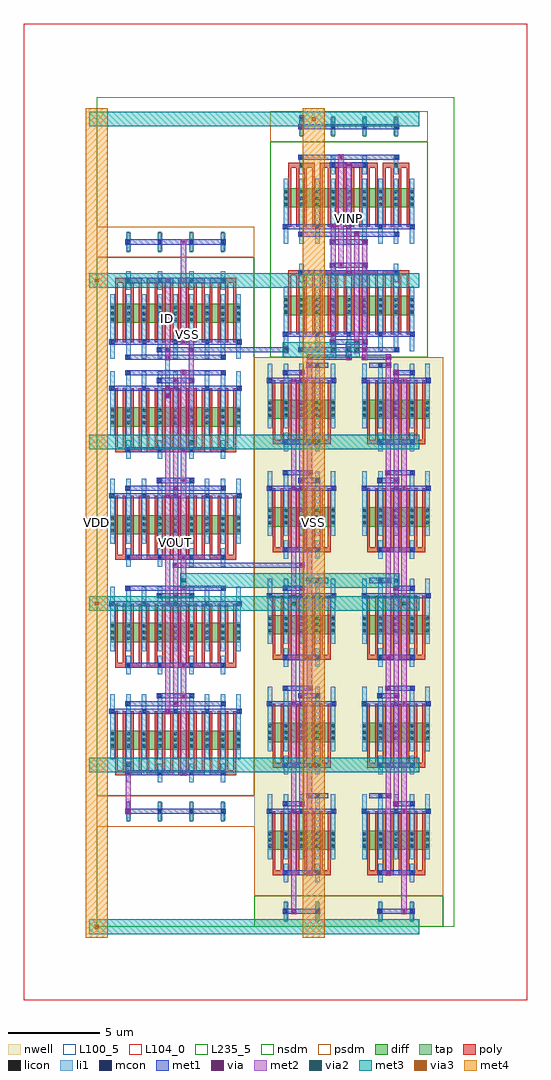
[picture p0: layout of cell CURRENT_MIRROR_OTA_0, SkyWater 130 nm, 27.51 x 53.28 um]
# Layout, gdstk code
from math import pi, radians
import gdstk
lib = gdstk.Library(unit=1e-6, precision=1e-09)
def R(c, l, rs):  # rectangles x0, y0, x1, y1
    for r in rs: c.add(gdstk.rectangle(r[:2], r[2:], *l))
def A(c, l, x, y, w, h, nx, ny, dx, dy):  # array of equal rectangles
    R(c, l, [(x+i*dx, y+j*dy, x+i*dx+w, y+j*dy+h) for i in range(nx) for j in range(ny)])
def P(c, l, *ps):  # polygons
    for p in ps: c.add(gdstk.Polygon(p, *l))
nwell = (64, 20)
diff = (65, 20)
tap = (65, 44)
poly = (66, 20)
licon = (66, 44)
li1 = (67, 20)
mcon = (67, 44)
met1 = (68, 20)
via = (68, 44)
met2 = (69, 20)
via2 = (69, 44)
met3 = (70, 20)
via3 = (70, 44)
met4 = (71, 20)
nsdm = (93, 44)
psdm = (94, 20)
L100_5 = (100, 5)
L104_0 = (104, 0)
L235_5 = (235, 5)

scm_nmos_5643887_x2_y1_1 = lib.new_cell('SCM_NMOS_5643887_X2_Y1_1724778739')
R(scm_nmos_5643887_x2_y1_1, diff, [(0.735,2.31,7.865,3.36)])
A(scm_nmos_5643887_x2_y1_1, tap, 1.635, 6.16, 0.17, 1.12, 4, 1, 1.72, 0)
A(scm_nmos_5643887_x2_y1_1, poly, 1, 1.26, 0.15, 3.36, 16, 1, 0.43, 0)
A(scm_nmos_5643887_x2_y1_1, poly, 1, 4.485, 1.44, 0.27, 4, 1, 1.72, 0)
A(scm_nmos_5643887_x2_y1_1, licon, 0.775, 2.39, 0.17, 0.17, 3, 3, 0.86, 0.34)
A(scm_nmos_5643887_x2_y1_1, licon, 2.495, 2.39, 0.17, 0.17, 3, 3, 0.86, 0.34)
A(scm_nmos_5643887_x2_y1_1, licon, 4.215, 2.39, 0.17, 0.17, 3, 3, 0.86, 0.34)
A(scm_nmos_5643887_x2_y1_1, licon, 5.935, 2.39, 0.17, 0.17, 3, 3, 0.86, 0.34)
A(scm_nmos_5643887_x2_y1_1, licon, 1.635, 4.535, 0.17, 0.17, 4, 2, 1.72, 2.1)
A(scm_nmos_5643887_x2_y1_1, li1, 0.735, 0.335, 0.25, 3.53, 9, 1, 0.86, 0)
A(scm_nmos_5643887_x2_y1_1, li1, 1.595, 4.115, 0.25, 1.01, 4, 2, 1.72, 2.1)
A(scm_nmos_5643887_x2_y1_1, mcon, 0.775, 1.175, 0.17, 0.17, 5, 1, 1.72, 0)
A(scm_nmos_5643887_x2_y1_1, mcon, 1.635, 4.535, 0.17, 0.17, 4, 2, 1.72, 2.1)
R(scm_nmos_5643887_x2_y1_1, mcon, [(1.635,0.335,1.805,0.505), (6.795,0.335,6.965,0.505), (3.355,0.755,3.525,0.925), (5.075,0.755,5.245,0.925)])
R(scm_nmos_5643887_x2_y1_1, met1, [(1.55,0.28,7.05,0.56), (3.27,0.7,5.33,0.98), (0.69,1.12,7.91,1.4), (1.55,4.48,7.05,4.76), (1.55,6.58,7.05,6.86)])
R(scm_nmos_5643887_x2_y1_1, via, [(3.795,0.345,3.945,0.495), (4.655,1.185,4.805,1.335), (3.795,4.545,3.945,4.695), (4.655,6.645,4.805,6.795)])
R(scm_nmos_5643887_x2_y1_1, met2, [(3.73,0.26,4.01,4.78), (4.59,1.1,4.87,6.88)])
R(scm_nmos_5643887_x2_y1_1, nsdm, [(0,0,8.6,5.88)])
R(scm_nmos_5643887_x2_y1_1, psdm, [(0,5.88,8.6,7.56)])
R(scm_nmos_5643887_x2_y1_1, L100_5, [(0,0,8.6,7.56)])

scm_pmos_85912433_x1_y5_ = lib.new_cell('SCM_PMOS_85912433_X1_Y5_1724778741')
R(scm_pmos_85912433_x1_y5_, nwell, [(0,0,5.16,31.08)])
A(scm_pmos_85912433_x1_y5_, diff, 0.735, 2.31, 3.69, 1.05, 1, 5, 0, 5.88)
R(scm_pmos_85912433_x1_y5_, tap, [(1.635,29.68,1.805,30.8), (3.355,29.68,3.525,30.8)])
A(scm_pmos_85912433_x1_y5_, poly, 1, 1.26, 0.15, 3.36, 8, 5, 0.43, 5.88)
A(scm_pmos_85912433_x1_y5_, poly, 1, 4.485, 1.44, 0.27, 1, 5, 0, 5.88)
A(scm_pmos_85912433_x1_y5_, poly, 2.72, 4.485, 1.44, 0.27, 1, 5, 0, 5.88)
A(scm_pmos_85912433_x1_y5_, licon, 0.775, 2.39, 0.17, 0.17, 3, 3, 0.86, 0.34)
A(scm_pmos_85912433_x1_y5_, licon, 2.495, 2.39, 0.17, 0.17, 3, 3, 0.86, 0.34)
A(scm_pmos_85912433_x1_y5_, licon, 1.635, 4.535, 0.17, 0.17, 1, 5, 0, 5.88)
A(scm_pmos_85912433_x1_y5_, licon, 3.355, 4.535, 0.17, 0.17, 1, 5, 0, 5.88)
A(scm_pmos_85912433_x1_y5_, licon, 0.775, 8.27, 0.17, 0.17, 3, 3, 0.86, 0.34)
A(scm_pmos_85912433_x1_y5_, licon, 2.495, 8.27, 0.17, 0.17, 3, 3, 0.86, 0.34)
A(scm_pmos_85912433_x1_y5_, licon, 0.775, 14.15, 0.17, 0.17, 3, 3, 0.86, 0.34)
A(scm_pmos_85912433_x1_y5_, licon, 2.495, 14.15, 0.17, 0.17, 3, 3, 0.86, 0.34)
A(scm_pmos_85912433_x1_y5_, licon, 0.775, 20.03, 0.17, 0.17, 3, 3, 0.86, 0.34)
A(scm_pmos_85912433_x1_y5_, licon, 2.495, 20.03, 0.17, 0.17, 3, 3, 0.86, 0.34)
A(scm_pmos_85912433_x1_y5_, licon, 0.775, 25.91, 0.17, 0.17, 3, 3, 0.86, 0.34)
A(scm_pmos_85912433_x1_y5_, licon, 2.495, 25.91, 0.17, 0.17, 3, 3, 0.86, 0.34)
R(scm_pmos_85912433_x1_y5_, licon, [(1.635,30.155,1.805,30.325), (1.635,30.155,1.805,30.325), (1.635,30.155,1.805,30.325), (1.635,30.155,1.805,30.325), (1.635,30.155,1.805,30.325), (3.355,30.155,3.525,30.325), (3.355,30.155,3.525,30.325), (3.355,30.155,3.525,30.325), (3.355,30.155,3.525,30.325), (3.355,30.155,3.525,30.325)])
A(scm_pmos_85912433_x1_y5_, li1, 0.735, 0.335, 0.25, 3.53, 5, 5, 0.86, 5.88)
A(scm_pmos_85912433_x1_y5_, li1, 1.595, 4.115, 0.25, 1.01, 1, 5, 0, 5.88)
A(scm_pmos_85912433_x1_y5_, li1, 3.315, 4.115, 0.25, 1.01, 1, 5, 0, 5.88)
R(scm_pmos_85912433_x1_y5_, li1, [(1.595,29.735,1.845,30.745), (3.315,29.735,3.565,30.745)])
A(scm_pmos_85912433_x1_y5_, mcon, 0.775, 1.175, 0.17, 0.17, 3, 5, 1.72, 5.88)
R(scm_pmos_85912433_x1_y5_, mcon, [(1.635,0.335,1.805,0.505), (3.355,0.755,3.525,0.925), (1.635,4.535,1.805,4.705), (3.355,4.535,3.525,4.705), (3.355,6.215,3.525,6.385), (1.635,6.635,1.805,6.805), (1.635,10.415,1.805,10.585), (3.355,10.415,3.525,10.585), (1.635,12.095,1.805,12.265), (3.355,12.515,3.525,12.685), (1.635,16.295,1.805,16.465), (3.355,16.295,3.525,16.465), (3.355,17.975,3.525,18.145), (1.635,18.395,1.805,18.565), (1.635,22.175,1.805,22.345), (3.355,22.175,3.525,22.345), (1.635,23.855,1.805,24.025), (3.355,24.275,3.525,24.445), (1.635,28.055,1.805,28.225), (3.355,28.055,3.525,28.225), (1.635,30.155,1.805,30.325), (3.355,30.155,3.525,30.325)])
A(scm_pmos_85912433_x1_y5_, met1, 1.12, 0.28, 1.2, 0.28, 1, 3, 0, 11.76)
A(scm_pmos_85912433_x1_y5_, met1, 2.41, 0.7, 1.2, 0.28, 1, 3, 0, 11.76)
A(scm_pmos_85912433_x1_y5_, met1, 0.69, 1.12, 3.78, 0.28, 1, 5, 0, 5.88)
A(scm_pmos_85912433_x1_y5_, met1, 1.55, 4.48, 2.06, 0.28, 1, 5, 0, 5.88)
R(scm_pmos_85912433_x1_y5_, met1, [(1.98,6.16,3.61,6.44), (1.55,6.58,2.75,6.86), (1.98,17.92,3.61,18.2), (1.55,18.34,2.75,18.62), (1.55,30.1,3.61,30.38)])
A(scm_pmos_85912433_x1_y5_, via, 2.505, 0.765, 0.15, 0.15, 1, 5, 0, 5.88)
A(scm_pmos_85912433_x1_y5_, via, 2.935, 1.185, 0.15, 0.15, 1, 5, 0, 5.88)
R(scm_pmos_85912433_x1_y5_, via, [(2.075,0.345,2.225,0.495), (2.075,4.545,2.225,4.695), (2.075,6.225,2.225,6.375), (2.075,10.425,2.225,10.575), (2.075,12.105,2.225,12.255), (2.075,16.305,2.225,16.455), (2.075,17.985,2.225,18.135), (2.075,22.185,2.225,22.335), (2.075,23.865,2.225,24.015), (2.075,28.065,2.225,28.215), (2.935,30.165,3.085,30.315)])
R(scm_pmos_85912433_x1_y5_, met2, [(2.01,0.26,2.29,28.3), (2.44,0.68,2.72,24.52), (2.87,1.1,3.15,30.4)])
R(scm_pmos_85912433_x1_y5_, nsdm, [(0,29.4,5.16,31.08)])
R(scm_pmos_85912433_x1_y5_, psdm, [(0,0,5.16,29.4)])
R(scm_pmos_85912433_x1_y5_, L100_5, [(0,0,5.16,31.08)])

scm_nmos_b_85279373_x2_y = lib.new_cell('SCM_NMOS_B_85279373_X2_Y4_1724778740')
A(scm_nmos_b_85279373_x2_y, diff, 0.735, 2.31, 7.13, 1.05, 1, 4, 0, 5.88)
A(scm_nmos_b_85279373_x2_y, tap, 1.635, 23.8, 0.17, 1.12, 4, 1, 1.72, 0)
A(scm_nmos_b_85279373_x2_y, poly, 1, 1.26, 0.15, 3.36, 16, 4, 0.43, 5.88)
A(scm_nmos_b_85279373_x2_y, poly, 1, 4.485, 1.44, 0.27, 4, 4, 1.72, 5.88)
A(scm_nmos_b_85279373_x2_y, licon, 0.775, 2.39, 0.17, 0.17, 3, 3, 0.86, 0.34)
A(scm_nmos_b_85279373_x2_y, licon, 2.495, 2.39, 0.17, 0.17, 3, 3, 0.86, 0.34)
A(scm_nmos_b_85279373_x2_y, licon, 4.215, 2.39, 0.17, 0.17, 3, 3, 0.86, 0.34)
A(scm_nmos_b_85279373_x2_y, licon, 5.935, 2.39, 0.17, 0.17, 3, 3, 0.86, 0.34)
A(scm_nmos_b_85279373_x2_y, licon, 1.635, 4.535, 0.17, 0.17, 4, 4, 1.72, 5.88)
A(scm_nmos_b_85279373_x2_y, licon, 0.775, 8.27, 0.17, 0.17, 3, 3, 0.86, 0.34)
A(scm_nmos_b_85279373_x2_y, licon, 2.495, 8.27, 0.17, 0.17, 3, 3, 0.86, 0.34)
A(scm_nmos_b_85279373_x2_y, licon, 4.215, 8.27, 0.17, 0.17, 3, 3, 0.86, 0.34)
A(scm_nmos_b_85279373_x2_y, licon, 5.935, 8.27, 0.17, 0.17, 3, 3, 0.86, 0.34)
A(scm_nmos_b_85279373_x2_y, licon, 0.775, 14.15, 0.17, 0.17, 3, 3, 0.86, 0.34)
A(scm_nmos_b_85279373_x2_y, licon, 2.495, 14.15, 0.17, 0.17, 3, 3, 0.86, 0.34)
A(scm_nmos_b_85279373_x2_y, licon, 4.215, 14.15, 0.17, 0.17, 3, 3, 0.86, 0.34)
A(scm_nmos_b_85279373_x2_y, licon, 5.935, 14.15, 0.17, 0.17, 3, 3, 0.86, 0.34)
A(scm_nmos_b_85279373_x2_y, licon, 0.775, 20.03, 0.17, 0.17, 3, 3, 0.86, 0.34)
A(scm_nmos_b_85279373_x2_y, licon, 2.495, 20.03, 0.17, 0.17, 3, 3, 0.86, 0.34)
A(scm_nmos_b_85279373_x2_y, licon, 4.215, 20.03, 0.17, 0.17, 3, 3, 0.86, 0.34)
A(scm_nmos_b_85279373_x2_y, licon, 5.935, 20.03, 0.17, 0.17, 3, 3, 0.86, 0.34)
R(scm_nmos_b_85279373_x2_y, licon, [(1.635,24.275,1.805,24.445), (1.635,24.275,1.805,24.445), (1.635,24.275,1.805,24.445), (1.635,24.275,1.805,24.445), (3.355,24.275,3.525,24.445), (3.355,24.275,3.525,24.445), (3.355,24.275,3.525,24.445), (3.355,24.275,3.525,24.445), (5.075,24.275,5.245,24.445), (5.075,24.275,5.245,24.445), (5.075,24.275,5.245,24.445), (5.075,24.275,5.245,24.445), (6.795,24.275,6.965,24.445), (6.795,24.275,6.965,24.445), (6.795,24.275,6.965,24.445), (6.795,24.275,6.965,24.445)])
A(scm_nmos_b_85279373_x2_y, li1, 0.735, 0.335, 0.25, 3.53, 9, 4, 0.86, 5.88)
A(scm_nmos_b_85279373_x2_y, li1, 1.595, 4.115, 0.25, 1.01, 4, 4, 1.72, 5.88)
A(scm_nmos_b_85279373_x2_y, li1, 1.595, 23.855, 0.25, 1.01, 4, 1, 1.72, 0)
A(scm_nmos_b_85279373_x2_y, mcon, 0.775, 1.175, 0.17, 0.17, 5, 4, 1.72, 5.88)
A(scm_nmos_b_85279373_x2_y, mcon, 1.635, 4.535, 0.17, 0.17, 4, 4, 1.72, 5.88)
A(scm_nmos_b_85279373_x2_y, mcon, 1.635, 24.275, 0.17, 0.17, 4, 1, 1.72, 0)
R(scm_nmos_b_85279373_x2_y, mcon, [(1.635,0.335,1.805,0.505), (6.795,0.335,6.965,0.505), (3.355,0.755,3.525,0.925), (5.075,0.755,5.245,0.925), (3.355,6.215,3.525,6.385), (5.075,6.215,5.245,6.385), (1.635,6.635,1.805,6.805), (6.795,6.635,6.965,6.805), (1.635,12.095,1.805,12.265), (6.795,12.095,6.965,12.265), (3.355,12.515,3.525,12.685), (5.075,12.515,5.245,12.685), (3.355,17.975,3.525,18.145), (5.075,17.975,5.245,18.145), (1.635,18.395,1.805,18.565), (6.795,18.395,6.965,18.565)])
A(scm_nmos_b_85279373_x2_y, met1, 0.69, 1.12, 7.22, 0.28, 1, 4, 0, 5.88)
R(scm_nmos_b_85279373_x2_y, met1, [(1.55,0.28,7.05,0.56), (3.27,0.7,5.33,0.98), (1.55,4.48,7.05,4.76), (3.27,6.16,5.33,6.44), (1.55,6.58,7.05,6.86), (1.55,10.36,7.05,10.64), (1.55,12.04,7.05,12.32), (3.27,12.46,5.33,12.74), (1.55,16.24,7.05,16.52), (3.27,17.92,5.33,18.2), (1.55,18.34,7.05,18.62), (1.55,22.12,7.05,22.4), (1.55,24.22,7.05,24.5)])
A(scm_nmos_b_85279373_x2_y, via, 4.225, 0.765, 0.15, 0.15, 1, 4, 0, 5.88)
A(scm_nmos_b_85279373_x2_y, via, 4.655, 1.185, 0.15, 0.15, 1, 4, 0, 5.88)
R(scm_nmos_b_85279373_x2_y, via, [(3.795,0.345,3.945,0.495), (3.795,4.545,3.945,4.695), (3.795,6.225,3.945,6.375), (3.795,10.425,3.945,10.575), (3.795,12.105,3.945,12.255), (3.795,16.305,3.945,16.455), (3.795,17.985,3.945,18.135), (3.795,22.185,3.945,22.335)])
R(scm_nmos_b_85279373_x2_y, met2, [(3.73,0.26,4.01,22.42), (4.16,0.68,4.44,18.64), (4.59,1.1,4.87,19.06)])
R(scm_nmos_b_85279373_x2_y, nsdm, [(0,0,8.6,23.52)])
R(scm_nmos_b_85279373_x2_y, psdm, [(0,23.52,8.6,25.2)])
R(scm_nmos_b_85279373_x2_y, L100_5, [(0,0,8.6,25.2)])

dp_nmos_b_6171529_x2_y2_ = lib.new_cell('DP_NMOS_B_6171529_X2_Y2_1724778738')
R(dp_nmos_b_6171529_x2_y2_, diff, [(0.735,2.31,7.865,3.36), (0.735,8.19,7.865,9.24)])
A(dp_nmos_b_6171529_x2_y2_, tap, 1.635, 12.04, 0.17, 1.12, 4, 1, 1.72, 0)
A(dp_nmos_b_6171529_x2_y2_, poly, 1, 1.26, 0.15, 3.36, 16, 2, 0.43, 5.88)
A(dp_nmos_b_6171529_x2_y2_, poly, 1, 4.485, 1.44, 0.27, 4, 2, 1.72, 5.88)
A(dp_nmos_b_6171529_x2_y2_, licon, 0.775, 2.39, 0.17, 0.17, 3, 3, 0.86, 0.34)
A(dp_nmos_b_6171529_x2_y2_, licon, 2.495, 2.39, 0.17, 0.17, 3, 3, 0.86, 0.34)
A(dp_nmos_b_6171529_x2_y2_, licon, 4.215, 2.39, 0.17, 0.17, 3, 3, 0.86, 0.34)
A(dp_nmos_b_6171529_x2_y2_, licon, 5.935, 2.39, 0.17, 0.17, 3, 3, 0.86, 0.34)
A(dp_nmos_b_6171529_x2_y2_, licon, 1.635, 4.535, 0.17, 0.17, 4, 2, 1.72, 5.88)
A(dp_nmos_b_6171529_x2_y2_, licon, 0.775, 8.27, 0.17, 0.17, 3, 3, 0.86, 0.34)
A(dp_nmos_b_6171529_x2_y2_, licon, 2.495, 8.27, 0.17, 0.17, 3, 3, 0.86, 0.34)
A(dp_nmos_b_6171529_x2_y2_, licon, 4.215, 8.27, 0.17, 0.17, 3, 3, 0.86, 0.34)
A(dp_nmos_b_6171529_x2_y2_, licon, 5.935, 8.27, 0.17, 0.17, 3, 3, 0.86, 0.34)
R(dp_nmos_b_6171529_x2_y2_, licon, [(1.635,12.515,1.805,12.685), (1.635,12.515,1.805,12.685), (3.355,12.515,3.525,12.685), (3.355,12.515,3.525,12.685), (5.075,12.515,5.245,12.685), (5.075,12.515,5.245,12.685), (6.795,12.515,6.965,12.685), (6.795,12.515,6.965,12.685)])
A(dp_nmos_b_6171529_x2_y2_, li1, 0.735, 0.335, 0.25, 3.53, 9, 2, 0.86, 5.88)
A(dp_nmos_b_6171529_x2_y2_, li1, 1.595, 4.115, 0.25, 1.01, 4, 2, 1.72, 5.88)
A(dp_nmos_b_6171529_x2_y2_, li1, 1.595, 12.095, 0.25, 1.01, 4, 1, 1.72, 0)
A(dp_nmos_b_6171529_x2_y2_, mcon, 0.775, 1.175, 0.17, 0.17, 5, 2, 1.72, 5.88)
A(dp_nmos_b_6171529_x2_y2_, mcon, 1.635, 12.515, 0.17, 0.17, 4, 1, 1.72, 0)
R(dp_nmos_b_6171529_x2_y2_, mcon, [(1.635,0.335,1.805,0.505), (6.795,0.335,6.965,0.505), (3.355,0.755,3.525,0.925), (5.075,0.755,5.245,0.925), (1.635,4.535,1.805,4.705), (6.795,4.535,6.965,4.705), (3.355,4.955,3.525,5.125), (5.075,4.955,5.245,5.125), (3.355,6.215,3.525,6.385), (5.075,6.215,5.245,6.385), (1.635,6.635,1.805,6.805), (6.795,6.635,6.965,6.805), (3.355,10.415,3.525,10.585), (5.075,10.415,5.245,10.585), (1.635,10.835,1.805,11.005), (6.795,10.835,6.965,11.005)])
R(dp_nmos_b_6171529_x2_y2_, met1, [(1.55,0.28,7.05,0.56), (3.27,0.7,5.33,0.98), (0.69,1.12,7.91,1.4), (1.55,4.48,7.05,4.76), (3.27,4.9,5.33,5.18), (3.27,6.16,5.33,6.44), (1.55,6.58,7.05,6.86), (0.69,7,7.91,7.28), (3.27,10.36,5.33,10.64), (1.55,10.78,7.05,11.06), (1.55,12.46,7.05,12.74)])
R(dp_nmos_b_6171529_x2_y2_, via, [(3.365,0.345,3.515,0.495), (3.795,0.765,3.945,0.915), (5.085,1.185,5.235,1.335), (4.225,4.545,4.375,4.695), (4.655,4.965,4.805,5.115), (3.365,6.225,3.515,6.375), (3.795,6.645,3.945,6.795), (5.085,7.065,5.235,7.215), (4.225,10.425,4.375,10.575), (4.655,10.845,4.805,10.995)])
R(dp_nmos_b_6171529_x2_y2_, met2, [(3.3,0.26,3.58,6.46), (3.73,0.68,4.01,6.88), (5.02,1.1,5.3,7.3), (4.16,4.46,4.44,10.66), (4.59,4.88,4.87,11.08)])
R(dp_nmos_b_6171529_x2_y2_, nsdm, [(0,0,8.6,11.76)])
R(dp_nmos_b_6171529_x2_y2_, psdm, [(0,11.76,8.6,13.44)])
R(dp_nmos_b_6171529_x2_y2_, L100_5, [(0,0,8.6,13.44)])

current_mirror_ota_0 = lib.new_cell('CURRENT_MIRROR_OTA_0')
R(current_mirror_ota_0, li1, [(3.745,28.895,3.995,29.065), (3.745,28.98,3.995,31.5), (3.745,31.415,3.995,31.585), (3.745,31.415,3.995,31.585), (3.745,31.415,3.995,31.585), (3.745,31.415,3.995,31.585)])
R(current_mirror_ota_0, mcon, [(3.785,28.895,3.955,29.065), (3.785,31.415,3.955,31.585), (3.785,31.415,3.955,31.585), (3.785,31.415,3.955,31.585), (3.785,31.415,3.955,31.585)])
R(current_mirror_ota_0, met1, [(1.56,6.16,1.88,6.44), (1.56,6.16,1.88,6.44), (1.56,6.16,1.88,6.44), (4.14,19.6,4.46,19.88), (4.14,19.6,4.46,19.88), (4.3,19.6,11.18,19.88), (11.02,19.6,11.34,19.88), (11.02,19.6,11.34,19.88), (3.7,28.84,4.04,29.12), (3.71,28.84,4.03,29.12), (3.721,28.84,4.019,29.12), (11.45,30.94,11.77,31.22), (11.45,30.94,11.77,31.22), (11.61,30.94,13.76,31.22), (13.6,30.94,13.92,31.22), (13.6,30.94,13.92,31.22), (14.46,30.94,14.78,31.22), (14.46,30.94,14.78,31.22), (14.62,30.94,15.91,31.22), (15.75,30.94,16.07,31.22), (15.75,30.94,16.07,31.22), (3.7,31.36,4.04,31.64), (3.7,31.36,4.04,31.64), (3.7,31.36,4.04,31.64), (3.7,31.36,4.04,31.64), (5.16,31.36,10.32,31.64), (10.16,31.36,10.48,31.64), (4.57,32.2,4.89,32.48), (4.57,32.2,4.89,32.48), (4.57,32.2,4.89,32.48), (4.57,32.2,4.89,32.48), (4.73,32.2,5.16,32.48), (5,32.2,5.32,32.48), (5,32.2,5.32,32.48), (5,32.2,5.32,32.48), (5,32.2,5.32,32.48), (11.02,43.54,11.34,43.82), (11.02,43.54,11.34,43.82)])
P(current_mirror_ota_0, met1, [(0,0),(0,0),(0,0),(0,0)],
  [(0,0),(0,0),(0,0),(0,0)],
  [(0,0),(0,0),(0,0),(0,0)])
R(current_mirror_ota_0, via, [(1.645,6.225,1.795,6.375), (1.645,6.225,1.795,6.375), (1.645,6.225,1.795,6.375), (4.225,19.665,4.375,19.815), (4.225,19.665,4.375,19.815), (11.105,19.665,11.255,19.815), (11.105,19.665,11.255,19.815), (3.795,28.905,3.945,29.055), (11.535,31.005,11.685,31.155), (11.535,31.005,11.685,31.155), (13.685,31.005,13.835,31.155), (13.685,31.005,13.835,31.155), (14.545,31.005,14.695,31.155), (14.545,31.005,14.695,31.155), (15.835,31.005,15.985,31.155), (15.835,31.005,15.985,31.155), (10.245,31.425,10.395,31.575), (4.655,32.265,4.805,32.415), (4.655,32.265,4.805,32.415), (4.655,32.265,4.805,32.415), (4.655,32.265,4.805,32.415), (5.085,32.265,5.235,32.415), (5.085,32.265,5.235,32.415), (5.085,32.265,5.235,32.415), (5.085,32.265,5.235,32.415), (11.105,43.605,11.255,43.755), (11.105,43.605,11.255,43.755)])
R(current_mirror_ota_0, met2, [(1.58,6.14,1.86,6.46), (1.58,6.14,1.86,6.46), (1.58,6.14,1.86,6.46), (1.58,6.3,1.86,8.82), (1.58,8.635,1.86,9.005), (1.58,8.635,1.86,9.005), (1.58,8.635,1.86,9.005), (10.61,17.455,10.89,17.825), (10.61,17.455,10.89,17.825), (16.63,17.455,16.91,17.825), (16.63,17.455,16.91,17.825), (16.63,17.455,16.91,17.825), (4.59,18.715,4.87,19.085), (4.59,18.715,4.87,19.085), (16.2,18.715,16.48,19.085), (16.2,18.715,16.48,19.085), (4.16,19.58,4.44,19.9), (4.16,19.58,4.44,19.9), (11.04,19.58,11.32,19.9), (11.04,19.58,11.32,19.9), (5.02,26.275,5.3,26.645), (5.02,26.275,5.3,26.645), (5.02,26.275,5.3,26.645), (5.02,26.275,5.3,26.645), (5.02,26.46,5.3,32.34), (3.73,28.82,4.01,29.14), (11.47,30.66,11.75,31.08), (15.77,30.66,16.05,31.08), (11.47,30.92,11.75,31.24), (11.47,30.92,11.75,31.24), (13.62,30.92,13.9,31.24), (13.62,30.92,13.9,31.24), (14.48,30.92,14.76,31.24), (14.48,30.92,14.76,31.24), (15.77,30.92,16.05,31.24), (15.77,30.92,16.05,31.24), (13.62,31.08,13.9,31.5), (14.48,31.08,14.76,31.5), (10.18,31.315,10.46,31.685), (12.76,31.315,13.04,31.685), (12.76,31.315,13.04,31.685), (13.62,31.315,13.9,31.685), (13.62,31.315,13.9,31.685), (14.05,31.315,14.33,31.685), (14.05,31.315,14.33,31.685), (10.18,31.34,10.46,31.66), (10.18,31.379,10.46,31.621), (12.76,31.5,13.04,32.34), (14.05,31.5,14.33,31.92), (4.59,32.18,4.87,32.5), (4.59,32.18,4.87,32.5), (4.59,32.18,4.87,32.5), (4.59,32.18,4.87,32.5), (5.02,32.18,5.3,32.5), (5.02,32.18,5.3,32.5), (5.02,32.18,5.3,32.5), (5.02,32.18,5.3,32.5), (11.04,43.52,11.32,43.84), (11.04,43.52,11.32,43.84), (11.04,43.68,11.32,44.1), (11.04,43.915,11.32,44.285), (11.04,43.915,11.32,44.285)])
P(current_mirror_ota_0, met2, [(0,0),(0,0),(0,0),(0,0)],
  [(0,0),(0,0),(0,0),(0,0)],
  [(0,0),(0,0),(0,0),(0,0)],
  [(0,0),(0,0),(0,0),(0,0)],
  [(0,0),(0,0),(0,0),(0,0)],
  [(0,0),(0,0),(0,0),(0,0)],
  [(0,0),(0,0),(0,0),(0,0)],
  [(0,0),(0,0),(0,0),(0,0)],
  [(0,0),(0,0),(0,0),(0,0)],
  [(0,0),(0,0),(0,0),(0,0)],
  [(0,0),(0,0),(0,0),(0,0)],
  [(0,0),(0,0),(0,0),(0,0)],
  [(0,0),(0,0),(0,0),(0,0)],
  [(0,0),(0,0),(0,0),(0,0)],
  [(0,0),(0,0),(0,0),(0,0)],
  [(0,0),(0,0),(0,0),(0,0)],
  [(0,0),(0,0),(0,0),(0,0)],
  [(0,0),(0,0),(0,0),(0,0)],
  [(0,0),(0,0),(0,0),(0,0)],
  [(0,0),(0,0),(0,0),(0,0)])
R(current_mirror_ota_0, via2, [(1.62,8.72,1.82,8.92), (1.62,8.72,1.82,8.92), (1.62,8.72,1.82,8.92), (10.65,17.54,10.85,17.74), (10.65,17.54,10.85,17.74), (16.67,17.54,16.87,17.74), (16.67,17.54,16.87,17.74), (16.67,17.54,16.87,17.74), (4.63,18.8,4.83,19), (4.63,18.8,4.83,19), (16.24,18.8,16.44,19), (16.24,18.8,16.44,19), (5.06,26.36,5.26,26.56), (5.06,26.36,5.26,26.56), (5.06,26.36,5.26,26.56), (5.06,26.36,5.26,26.56), (10.22,31.4,10.42,31.6), (12.8,31.4,13,31.6), (12.8,31.4,13,31.6), (13.66,31.4,13.86,31.6), (13.66,31.4,13.86,31.6), (14.09,31.4,14.29,31.6), (14.09,31.4,14.29,31.6), (11.08,44,11.28,44.2), (11.08,44,11.28,44.2)])
A(current_mirror_ota_0, met3, -0.4, -0.4, 4.24, 0.8, 3, 6, 3.44, 8.82)
A(current_mirror_ota_0, met3, -0.165, -0.4, 0.33, 0.8, 1, 3, 0, 17.64)
A(current_mirror_ota_0, met3, 9.92, -0.4, 2.32, 0.8, 1, 6, 0, 8.82)
A(current_mirror_ota_0, met3, 11.44, -0.4, 2.72, 0.8, 1, 6, 0, 8.82)
A(current_mirror_ota_0, met3, 13.36, -0.4, 4.24, 0.8, 1, 6, 0, 8.82)
A(current_mirror_ota_0, met3, 11.675, 8.42, 0.33, 0.8, 1, 3, 0, 17.64)
R(current_mirror_ota_0, met3, [(1.555,8.42,1.885,9.22), (1.555,8.42,1.885,9.22), (1.555,8.42,1.885,9.22), (10.585,17.24,10.915,18.04), (10.585,17.24,10.915,18.04), (16.605,17.24,16.935,18.04), (16.605,17.24,16.935,18.04), (16.605,17.24,16.935,18.04), (4.565,18.5,4.895,19.3), (4.565,18.5,4.895,19.3), (4.73,18.5,16.34,19.3), (16.175,18.5,16.505,19.3), (16.175,18.5,16.505,19.3), (4.995,26.06,5.325,26.86), (4.995,26.06,5.325,26.86), (4.995,26.06,5.325,26.86), (4.995,26.06,5.325,26.86), (10.155,31.1,10.485,31.9), (10.32,31.1,12.9,31.9), (12.735,31.1,13.065,31.9), (12.735,31.1,13.065,31.9), (13.595,31.1,13.925,31.9), (13.595,31.1,13.925,31.9), (13.76,31.1,14.19,31.9), (14.025,31.1,14.355,31.9), (14.025,31.1,14.355,31.9), (11.015,43.7,11.345,44.5), (11.015,43.7,11.345,44.5)])
A(current_mirror_ota_0, via3, -0.1, -0.1, 0.2, 0.2, 1, 3, 0, 17.64)
A(current_mirror_ota_0, via3, 11.74, 8.72, 0.2, 0.2, 1, 3, 0, 17.64)
A(current_mirror_ota_0, met4, -0.59, -0.59, 1.18, 10, 1, 4, 0, 8.82)
A(current_mirror_ota_0, met4, 11.25, -0.59, 1.18, 10, 1, 4, 0, 8.82)
A(current_mirror_ota_0, met4, -0.59, -0.165, 1.18, 0.33, 1, 3, 0, 17.64)
A(current_mirror_ota_0, met4, 11.25, 8.655, 1.18, 0.33, 1, 3, 0, 17.64)
R(current_mirror_ota_0, met4, [(-0.59,34.69,0.59,39.79), (11.25,34.69,12.43,39.79), (-0.59,38.61,0.59,44.69), (11.25,38.61,12.43,44.69)])
R(current_mirror_ota_0, L104_0, [(-4,-4,23.51,49.28)])
R(current_mirror_ota_0, L235_5, [(0,0,19.51,45.28)])
current_mirror_ota_0.add(gdstk.Reference(scm_nmos_5643887_x2_y1_1, (0,30.66)))
current_mirror_ota_0.add(gdstk.Reference(scm_pmos_85912433_x1_y5_, (13.76,31.08), x_reflection=True))
current_mirror_ota_0.add(gdstk.Reference(scm_pmos_85912433_x1_y5_, (13.76,31.08), rotation=pi))
current_mirror_ota_0.add(gdstk.Reference(scm_nmos_b_85279373_x2_y, (8.6,30.66), rotation=pi))
current_mirror_ota_0.add(gdstk.Reference(dp_nmos_b_6171529_x2_y2_, (18.06,31.08), rotation=pi, x_reflection=True))
current_mirror_ota_0.add(gdstk.Label('ID', (3.87,33.18), layer=69, texttype=5))
current_mirror_ota_0.add(gdstk.Label('VOUT', (4.3,21), layer=69, texttype=5))
current_mirror_ota_0.add(gdstk.Label('VINP', (13.76,38.64), layer=69, texttype=5))
current_mirror_ota_0.add(gdstk.Label('VINN', (13.33,39.06), layer=69, texttype=5))
current_mirror_ota_0.add(gdstk.Label('VSS', (11.84,22.05), layer=71, texttype=5))
current_mirror_ota_0.add(gdstk.Label('VSS', (4.945,32.34), layer=68, texttype=5))
current_mirror_ota_0.add(gdstk.Label('VSS', (11.84,22.05), layer=71, texttype=5))
current_mirror_ota_0.add(gdstk.Label('VSS', (11.84,22.05), layer=71, texttype=5))
current_mirror_ota_0.add(gdstk.Label('VSS', (11.84,22.05), layer=71, texttype=5))
current_mirror_ota_0.add(gdstk.Label('VSS', (11.84,22.05), layer=71, texttype=5))
current_mirror_ota_0.add(gdstk.Label('VSS', (11.84,22.05), layer=71, texttype=5))
current_mirror_ota_0.add(gdstk.Label('VSS', (11.84,22.05), layer=71, texttype=5))
current_mirror_ota_0.add(gdstk.Label('VSS', (11.84,22.05), layer=71, texttype=5))
current_mirror_ota_0.add(gdstk.Label('VSS', (11.84,22.05), layer=71, texttype=5))
current_mirror_ota_0.add(gdstk.Label('VSS', (11.84,22.05), layer=71, texttype=5))
current_mirror_ota_0.add(gdstk.Label('VDD', (0,22.05), layer=71, texttype=5))
current_mirror_ota_0.add(gdstk.Label('VDD', (0,22.05), layer=71, texttype=5))
current_mirror_ota_0.add(gdstk.Label('VDD', (0,22.05), layer=71, texttype=5))
current_mirror_ota_0.add(gdstk.Label('VDD', (0,22.05), layer=71, texttype=5))

lib.write_gds('CURRENT_MIRROR_OTA_0.gds')
